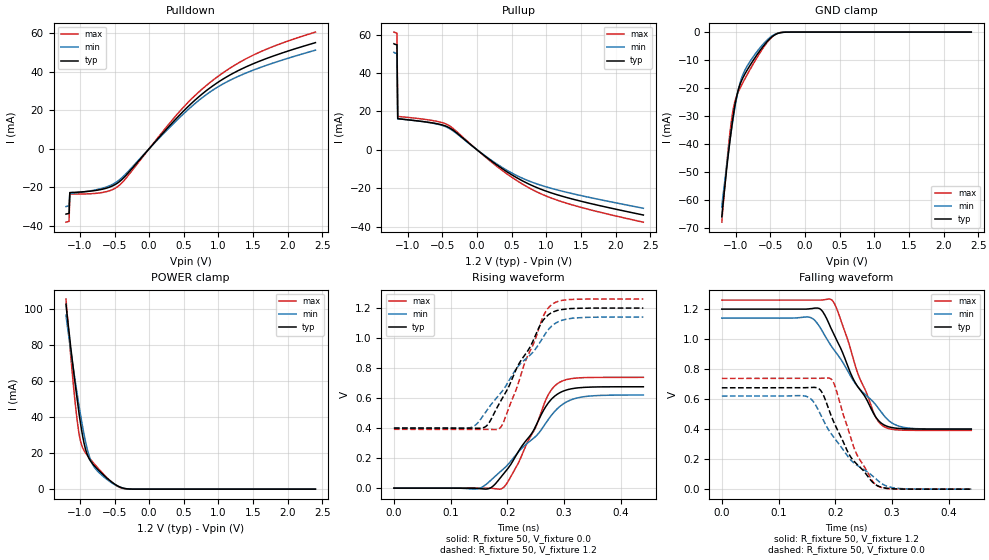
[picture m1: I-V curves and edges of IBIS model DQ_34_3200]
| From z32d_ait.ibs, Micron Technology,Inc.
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| MODEL DQ_34_3200 (34 Ohm Data I/O with no ODT, 1600-3200Mbps)
[Model]   DQ_34_3200
Model_type   I/O
Vinl = 905.000mV
Vinh = 1015.000mV
Vmeas = 960.000mV
Vref = 1200.000mV
Cref = 0.0pF
Rref = 50.000Ohm
|   typ   min   max
|C_comp   0.636pF   0.586pF   0.686pF
C_comp_pullup   0.318pF   0.293pF   0.343pF
C_comp_pulldown   0.318pF   0.293pF   0.343pF
[Model Spec]
| Timing spec test load voltage corners
Vref   1.2000V   1.1400V   1.2600V
| Dynamic Overshoot Parameters from DDR4 Specification
|D_overshoot_ampl_h   0.40   NA   NA
|D_overshoot_ampl_l   0.40   NA   NA
|D_overshoot_area_h   0.0800n   NA   NA
|D_overshoot_area_l   0.0800n   NA   NA
[Voltage Range]   1.2000V   1.1400V   1.2600V
| Junction Temperature (Ambient temp is 35C typ, 95C min, -40C max)
[Temperature Range]   50.0   110.0   -40.0
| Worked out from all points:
|   slope of the pulldown table from 0 to 0.18 V, typ, clamps not added: 24.5 ohm
|   slope of the pullup table from 0 to 0.18 V, typ, clamps not added: 35.6 ohm
|   GND clamp passes 1 mA (typ) near -0.44 V on its own axis
|   POWER clamp passes 1 mA (typ) near -0.41 V on its own axis
|   rising waveform, R_fixture 50, V_fixture 0.0: 20-80 % time 65.4ps typ, 88.1ps min, 51.3ps max; typ from 0 V to 0.675 V
|   rising waveform, R_fixture 50, V_fixture 1.2: 20-80 % time 66.8ps typ, 91.4ps min, 51.8ps max; typ from 0.4 V to 1.2 V
|   falling waveform, R_fixture 50, V_fixture 1.2: 20-80 % time 63.8ps typ, 87.8ps min, 48.9ps max; typ from 1.2 V to 0.4 V
|   falling waveform, R_fixture 50, V_fixture 0.0: 20-80 % time 59ps typ, 79.1ps min, 44.9ps max; typ from 0.676 V to 0 V
[Pulldown]
|   Voltage   I(typ)   I(min)   I(max)
-1.2V     -33.97mA   -30.06mA   -38.16mA
-1.156V   -33.6mA    -29.68mA   -37.79mA
-1.145V   -22.76mA   -23.2mA    -23.52mA
-676.4mV  -21.04mA   -20.54mA   -22.75mA
-545.5mV  -19.58mA   -18.83mA   -21.48mA
-436.4mV  -17.3mA    -16.38mA   -19.17mA
447.3mV   17.75mA    16.45mA    19.64mA
687.3mV   26.05mA    24.22mA    28.48mA
960mV     33.69mA    31.4mA     36.67mA
1.222V    39.38mA    36.53mA    43.11mA
1.527V    44.52mA    41.16mA    49.04mA
2.4V      55.1mA     51.2mA     60.58mA
[GND Clamp]
|   Voltage   I(typ)   I(min)   I(max)
-1.2V     -66.16mA   -62.66mA   -68.09mA
-1.135V   -50.09mA   -48.7mA    -48.84mA
-1.091V   -40.54mA   -40.34mA   -37.85mA
-1.047V   -32.06mA   -32.63mA   -29.28mA
-1.004V   -25.24mA   -25.89mA   -24.15mA
-938.2mV  -18.79mA   -18.38mA   -20.13mA
-850.9mV  -14.31mA   -12.88mA   -15.99mA
-643.6mV  -6.426mA   -5.46mA    -7.18mA
-458.2mV  -1.359mA   -1.119mA   -1.332mA
-381.8mV  -387.1uA   -326.7uA   -300.2uA
-250.9mV  -9.002uA   -11.12uA   1.741uA
2.4V      0A         0A         0A
[Pullup]
|   Voltage   I(typ)   I(min)   I(max)
-1.2V     55.21mA    50.73mA    61.29mA
-1.156V   54.64mA    50.13mA    60.76mA
-1.145V   16.26mA    16.13mA    17.4mA
-643.6mV  14.02mA    13.88mA    15.25mA
-414.5mV  11.76mA    11.38mA    12.86mA
-316.4mV  9.458mA    9.085mA    10.21mA
120mV     -3.407mA   -3.214mA   -3.711mA
370.9mV   -9.995mA   -9.341mA   -10.94mA
654.5mV   -16.13mA   -14.79mA   -17.81mA
960mV     -21.02mA   -18.86mA   -23.48mA
1.484V    -26.6mA    -23.68mA   -29.78mA
2.4V      -33.93mA   -30.41mA   -37.66mA
[POWER Clamp]
|   Voltage   I(typ)   I(min)   I(max)
-1.2V     102.5mA    96.48mA    105.3mA
-1.135V   79.77mA    77.75mA    75.19mA
-1.08V    62.13mA    63.23mA    52.54mA
-1.036V   48.91mA    52.15mA    37.32mA
-992.7mV  37.04mA    41.72mA    27.02mA
-916.4mV  21.89mA    26.01mA    20mA
-829.1mV  14.68mA    14.76mA    15.72mA
-730.9mV  10.5mA     9.465mA    11.33mA
-512.7mV  3.198mA    2.84mA     3.061mA
-392.7mV  773.5uA    737.7uA    533.9uA
-250.9mV  21.9uA     30.56uA    -1.736uA
2.4V      0A         0A         0A
[Ramp]
|   typ   min   max
| 20% - 80%
dV/dt_r   405.29m/65.42p   372.32m/88.07p   442.96m/51.27p
dV/dt_f   479.80m/63.86p   444.02m/87.85p   520.92m/48.87p
| Slew rate: Power terminated
|SR_r[V/ns]   7.18   4.86   10.05
|SR_f[V/ns]   7.51   5.05   10.66
| 25% - 75%
|dV/dt_r   337.74m/54.25p   310.27m/73.21p   369.13m/42.54p
|dV/dt_f   399.83m/53.48p   370.02m/73.44p   434.10m/40.83p
| Slew rate: Power terminated
|SR_r[V/ns]   7.13   4.78   9.99
|SR_f[V/ns]   7.48   5.04   10.63
R_load = 50
[Rising Waveform]
R_fixture = 50
V_fixture = 0.0
|   Time   V(typ)   V(min)   V(max)
0s        5.466uV    13.47uV    320nV
147ps     -1.706mV   -4.715mV   17.38uV
170ps     697.3uV    49.22mV    -380.1uV
190ps     79.57mV    117.2mV    -3.675mV
217ps     227.7mV    229.6mV    148mV
250ps     412.1mV    344.3mV    405.2mV
270ps     555.5mV    444.8mV    605.2mV
287ps     622.8mV    524.8mV    691.8mV
331ps     670.3mV    606.8mV    735.8mV
440ps     675.5mV    620.6mV    738.3mV
[Rising Waveform]
R_fixture   = 50
V_fixture   = 1.2
V_fixture_min = 1.14
V_fixture_max = 1.26
|   Time   V(typ)   V(min)   V(max)
0s        400.3mV    399.9mV    391.8mV
136ps     399.9mV    404.2mV    391.8mV
163ps     413.5mV    514.3mV    391.8mV
185ps     557.9mV    617.9mV    395.1mV
194ps     615.4mV    661.3mV    446mV
218ps     810.6mV    806.5mV    681.6mV
259ps     1.094V     980.3mV    1.102V
276ps     1.164V     1.072V     1.216V
316ps     1.197V     1.133V     1.258V
440ps     1.2V       1.14V      1.26V
[Falling Waveform]
R_fixture   = 50
V_fixture   = 1.2
V_fixture_min = 1.14
V_fixture_max = 1.26
|   Time   V(typ)   V(min)   V(max)
0s        1.2V       1.14V      1.26V
155ps     1.202V     1.146V     1.26V
175ps     1.196V     1.067V     1.26V
192ps     1.077V     960mV      1.265V
205ps     974.9mV    892.3mV    1.18V
233ps     725.6mV    717.6mV    853.4mV
268ps     502mV      578.1mV    507.4mV
281ps     440.7mV    514.9mV    430.7mV
320ps     402.7mV    412.6mV    393.1mV
440ps     400.3mV    400mV      391.8mV
[Falling Waveform]
R_fixture = 50
V_fixture = 0.0
|   Time   V(typ)   V(min)   V(max)
0s        675.5mV    620.6mV    738.3mV
150ps     676.7mV    617.1mV    738.3mV
174ps     659.6mV    497.8mV    738.8mV
191ps     507.9mV    380mV      738mV
200ps     426.2mV    333.1mV    682.6mV
224ps     235.1mV    208.9mV    385.9mV
236ps     175mV      165.6mV    248.3mV
272ps     28.24mV    67.34mV    28.54mV
310ps     1.328mV    5.559mV    665.5uV
440ps     5.568uV    15.11uV    4.257uV
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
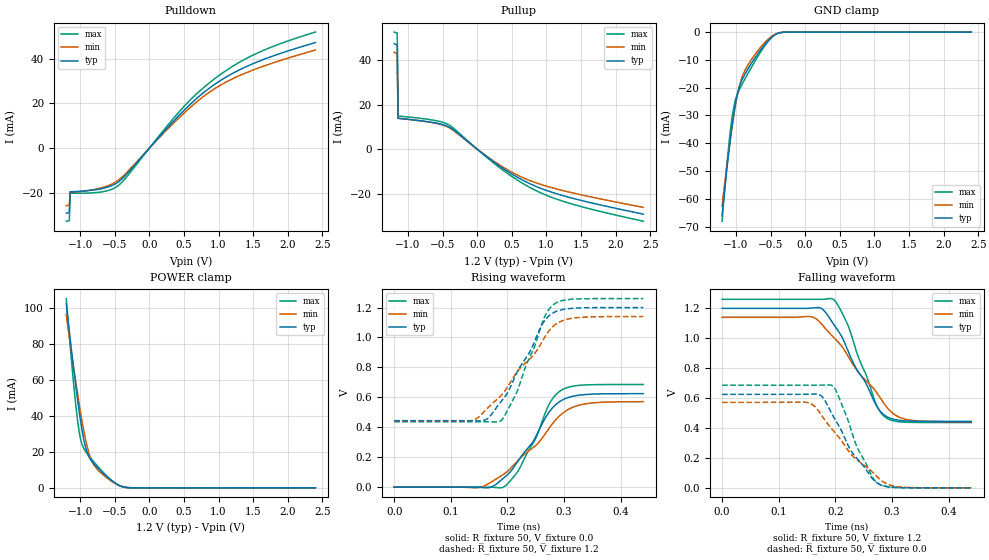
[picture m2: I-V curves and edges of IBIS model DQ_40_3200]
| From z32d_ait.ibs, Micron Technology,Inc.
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| MODEL DQ_40_3200 (40 Ohm Data I/O with no ODT, 1600-3200Mbps)
[Model]   DQ_40_3200
Model_type   I/O
Vinl = 905.000mV
Vinh = 1015.000mV
Vmeas = 960.000mV
Vref = 1200.000mV
Cref = 0.0pF
Rref = 50.000Ohm
|   typ   min   max
|C_comp   0.636pF   0.586pF   0.686pF
C_comp_pullup   0.318pF   0.293pF   0.343pF
C_comp_pulldown   0.318pF   0.293pF   0.343pF
[Model Spec]
| Timing spec test load voltage corners
Vref   1.2000V   1.1400V   1.2600V
| Dynamic Overshoot Parameters from DDR4 Specification
|D_overshoot_ampl_h   0.40   NA   NA
|D_overshoot_ampl_l   0.40   NA   NA
|D_overshoot_area_h   0.0800n   NA   NA
|D_overshoot_area_l   0.0800n   NA   NA
[Voltage Range]   1.2000V   1.1400V   1.2600V
| Junction Temperature (Ambient temp is 35C typ, 95C min, -40C max)
[Temperature Range]   50.0   110.0   -40.0
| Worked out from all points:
|   slope of the pulldown table from 0 to 0.18 V, typ, clamps not added: 28.6 ohm
|   slope of the pullup table from 0 to 0.18 V, typ, clamps not added: 41.6 ohm
|   GND clamp passes 1 mA (typ) near -0.44 V on its own axis
|   POWER clamp passes 1 mA (typ) near -0.41 V on its own axis
|   rising waveform, R_fixture 50, V_fixture 0.0: 20-80 % time 63.6ps typ, 84.2ps min, 49.8ps max; typ from 0 V to 0.625 V
|   rising waveform, R_fixture 50, V_fixture 1.2: 20-80 % time 62.3ps typ, 85.2ps min, 48.6ps max; typ from 0.444 V to 1.2 V
|   falling waveform, R_fixture 50, V_fixture 1.2: 20-80 % time 61.1ps typ, 84.5ps min, 46.3ps max; typ from 1.2 V to 0.444 V
|   falling waveform, R_fixture 50, V_fixture 0.0: 20-80 % time 60.7ps typ, 82.4ps min, 45.1ps max; typ from 0.625 V to 0 V
[Pulldown]
|   Voltage   I(typ)   I(min)   I(max)
-1.2V     -29.12mA   -25.76mA   -32.71mA
-1.156V   -28.8mA    -25.44mA   -32.39mA
-1.145V   -19.51mA   -19.88mA   -20.16mA
-698.2mV  -18.17mA   -17.78mA   -19.61mA
-447.3mV  -15.08mA   -14.3mA    -16.69mA
-338.2mV  -11.99mA   -11.26mA   -13.27mA
469.1mV   15.9mA     14.73mA    17.58mA
698.2mV   22.62mA    21.06mA    24.73mA
949.1mV   28.64mA    26.71mA    31.17mA
1.233V    33.94mA    31.47mA    37.16mA
1.527V    38.16mA    35.28mA    42.03mA
2.4V      47.23mA    43.88mA    51.93mA
[GND Clamp]
|   Voltage   I(typ)   I(min)   I(max)
-1.2V     -66.16mA   -62.66mA   -68.09mA
-1.135V   -50.09mA   -48.7mA    -48.84mA
-1.091V   -40.55mA   -40.34mA   -37.85mA
-1.047V   -32.05mA   -32.63mA   -29.3mA
-1.004V   -25.21mA   -25.91mA   -24.13mA
-970.9mV  -21.44mA   -21.67mA   -21.89mA
-927.3mV  -18.1mA    -17.42mA   -19.59mA
-850.9mV  -14.3mA    -12.88mA   -15.99mA
-632.7mV  -6.061mA   -5.136mA   -6.759mA
-447.3mV  -1.181mA   -961.6uA   -1.122mA
-250.9mV  -9.403uA   -12.65uA   310.9nA
2.4V      0A         0A         0A
[Pullup]
|   Voltage   I(typ)   I(min)   I(max)
-1.2V     47.33mA    43.48mA    52.54mA
-1.156V   46.84mA    42.97mA    52.08mA
-1.145V   13.94mA    13.83mA    14.91mA
-643.6mV  12.01mA    11.9mA     13.07mA
-425.5mV  10.24mA    9.925mA    11.21mA
-316.4mV  8.104mA    7.779mA    8.758mA
43.64mV   -1.073mA   -1.015mA   -1.164mA
370.9mV   -8.572mA   -8.003mA   -9.376mA
621.8mV   -13.28mA   -12.21mA   -14.64mA
960mV     -18.01mA   -16.17mA   -20.13mA
1.462V    -22.63mA   -20.14mA   -25.34mA
2.4V      -29.08mA   -26.07mA   -32.28mA
[POWER Clamp]
|   Voltage   I(typ)   I(min)   I(max)
-1.2V     102.5mA    96.48mA    105.3mA
-1.135V   79.77mA    77.75mA    75.19mA
-1.069V   58.73mA    60.41mA    48.42mA
-1.015V   42.78mA    46.83mA    31.4mA
-981.8mV  34.36mA    39.25mA    25.35mA
-938.2mV  25.27mA    30.08mA    21.3mA
-905.5mV  20.47mA    24.14mA    19.42mA
-818.2mV  14.14mA    13.89mA    15.22mA
-709.1mV  9.665mA    8.657mA    10.4mA
-501.8mV  2.908mA    2.591mA    2.742mA
-250.9mV  22.56uA    34.23uA    -929.3nA
2.4V      0A         0A         0A
[Ramp]
|   typ   min   max
| 20% - 80%
dV/dt_r   374.75m/63.58p   342.62m/84.23p   411.51m/49.79p
dV/dt_f   453.55m/61.15p   418.58m/84.59p   494.02m/46.30p
| 25% - 75%
|dV/dt_r   312.29m/52.61p   285.52m/70.40p   342.92m/41.18p
|dV/dt_f   377.96m/50.69p   348.81m/69.36p   411.68m/38.61p
R_load = 50
[Rising Waveform]
R_fixture = 50
V_fixture = 0.0
|   Time   V(typ)   V(min)   V(max)
0s        6.048uV    14.58uV    354.8nV
148ps     -1.045mV   -3.73mV    7.131uV
171ps     -47.82uV   33.03mV    -174.4uV
192ps     56.09mV    82.32mV    -1.231mV
220ps     183mV      183.4mV    115.5mV
250ps     337mV      278.3mV    326.2mV
273ps     498.3mV    390.8mV    549.3mV
292ps     570.9mV    476.1mV    639.7mV
336ps     618.4mV    555.5mV    682.6mV
440ps     624.6mV    571mV      685.8mV
[Rising Waveform]
R_fixture   = 50
V_fixture   = 1.2
V_fixture_min = 1.14
V_fixture_max = 1.26
|   Time   V(typ)   V(min)   V(max)
0s        444.1mV    442.3mV    436.6mV
137ps     443.8mV    445.3mV    436.6mV
164ps     455.2mV    524.7mV    436.6mV
187ps     563.5mV    604.8mV    440.8mV
215ps     752.6mV    760mV      620.6mV
240ps     907.8mV    857.9mV    872.9mV
264ps     1.104V     990.6mV    1.125V
279ps     1.161V     1.069V     1.213V
320ps     1.197V     1.132V     1.257V
440ps     1.2V       1.14V      1.26V
[Falling Waveform]
R_fixture   = 50
V_fixture   = 1.2
V_fixture_min = 1.14
V_fixture_max = 1.26
|   Time   V(typ)   V(min)   V(max)
0s        1.2V       1.14V      1.26V
156ps     1.201V     1.145V     1.26V
176ps     1.198V     1.093V     1.26V
195ps     1.104V     1.012V     1.263V
220ps     936.8mV    895.9mV    1.107V
270ps     566.7mV    651.7mV    576.7mV
286ps     487.8mV    563.5mV    478.6mV
304ps     457.1mV    491mV      446.5mV
327ps     446.9mV    455.9mV    438.2mV
440ps     444.1mV    442.4mV    436.6mV
[Falling Waveform]
R_fixture = 50
V_fixture = 0.0
|   Time   V(typ)   V(min)   V(max)
0s        624.6mV    571.2mV    685.9mV
151ps     625.4mV    569.7mV    685.8mV
175ps     614.8mV    488.2mV    686.2mV
193ps     500.6mV    397.3mV    685.8mV
203ps     434.8mV    352.8mV    635mV
229ps     239.7mV    219mV      371.8mV
241ps     184.3mV    178.6mV    251.3mV
275ps     29.84mV    69.66mV    30.19mV
313ps     1.736mV    6.587mV    945.6uV
440ps     6.181uV    17.23uV    368.3nV
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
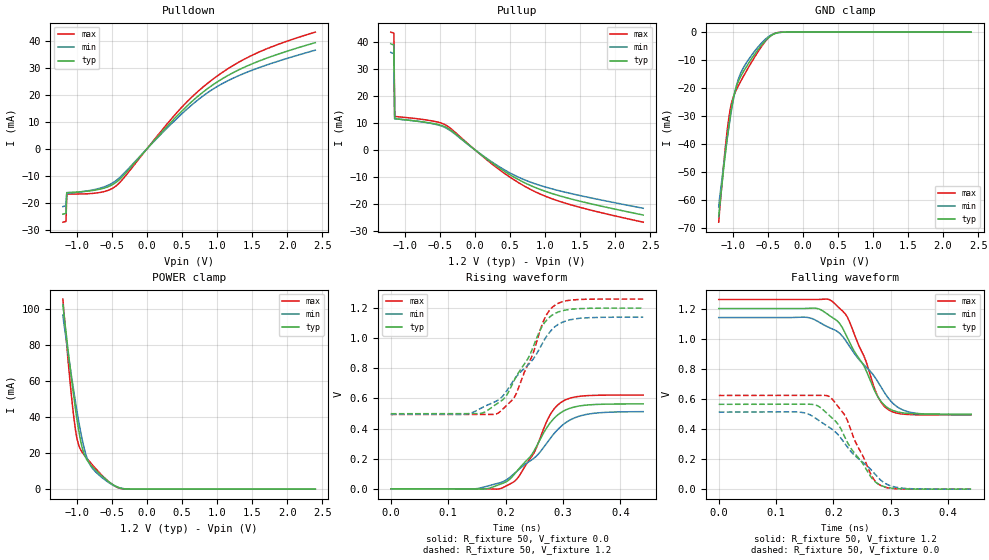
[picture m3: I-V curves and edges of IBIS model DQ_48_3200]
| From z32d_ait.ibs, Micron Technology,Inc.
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| MODEL DQ_48_3200 (48 Ohm Data I/O with no ODT, 1600-3200Mbps)
[Model]   DQ_48_3200
Model_type   I/O
Vinl = 905.000mV
Vinh = 1015.000mV
Vmeas = 960.000mV
Vref = 1200.000mV
Cref = 0.0pF
Rref = 50.000Ohm
|   typ   min   max
|C_comp   0.636pF   0.586pF   0.686pF
C_comp_pullup   0.318pF   0.293pF   0.343pF
C_comp_pulldown   0.318pF   0.293pF   0.343pF
[Model Spec]
| Timing spec test load voltage corners
Vref   1.2000V   1.1400V   1.2600V
| Dynamic Overshoot Parameters from DDR4 Specification
|D_overshoot_ampl_h   0.40   NA   NA
|D_overshoot_ampl_l   0.40   NA   NA
|D_overshoot_area_h   0.0800n   NA   NA
|D_overshoot_area_l   0.0800n   NA   NA
[Voltage Range]   1.2000V   1.1400V   1.2600V
| Junction Temperature (Ambient temp is 35C typ, 95C min, -40C max)
[Temperature Range]   50.0   110.0   -40.0
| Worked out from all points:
|   slope of the pulldown table from 0 to 0.18 V, typ, clamps not added: 34.3 ohm
|   slope of the pullup table from 0 to 0.18 V, typ, clamps not added: 49.8 ohm
|   GND clamp passes 1 mA (typ) near -0.44 V on its own axis
|   POWER clamp passes 1 mA (typ) near -0.41 V on its own axis
|   rising waveform, R_fixture 50, V_fixture 0.0: 20-80 % time 61.7ps typ, 79.8ps min, 48.6ps max; typ from 0 V to 0.564 V
|   rising waveform, R_fixture 50, V_fixture 1.2: 20-80 % time 56.5ps typ, 74.2ps min, 45ps max; typ from 0.499 V to 1.2 V
|   falling waveform, R_fixture 50, V_fixture 1.2: 20-80 % time 56.4ps typ, 75.3ps min, 45.2ps max; typ from 1.2 V to 0.499 V
|   falling waveform, R_fixture 50, V_fixture 0.0: 20-80 % time 56.3ps typ, 78.7ps min, 43.6ps max; typ from 0.564 V to 0 V
[Pulldown]
|   Voltage   I(typ)   I(min)   I(max)
-1.2V     -24.27mA   -21.47mA   -27.26mA
-1.156V   -24mA      -21.2mA    -26.99mA
-1.145V   -16.26mA   -16.57mA   -16.8mA
-665.5mV  -14.96mA   -14.59mA   -16.2mA
-545.5mV  -13.99mA   -13.45mA   -15.35mA
-436.4mV  -12.37mA   -11.7mA    -13.68mA
425.5mV   12.1mA     11.21mA    13.4mA
643.6mV   17.6mA     16.36mA    19.29mA
927.3mV   23.48mA    21.9mA     25.55mA
1.2V      27.83mA    25.82mA    30.45mA
1.527V    31.8mA     29.41mA    35.03mA
2.4V      39.36mA    36.57mA    43.27mA
[GND Clamp]
|   Voltage   I(typ)   I(min)   I(max)
-1.2V     -66.16mA   -62.66mA   -68.09mA
-1.135V   -50.09mA   -48.7mA    -48.85mA
-1.091V   -40.54mA   -40.34mA   -37.85mA
-1.058V   -34.05mA   -34.49mA   -31.11mA
-1.015V   -26.75mA   -27.46mA   -25.14mA
-981.8mV  -22.6mA    -23mA      -22.55mA
-949.1mV  -19.59mA   -19.34mA   -20.69mA
-861.8mV  -14.78mA   -13.39mA   -16.49mA
-654.5mV  -6.796mA   -5.791mA   -7.607mA
-458.2mV  -1.354mA   -1.107mA   -1.328mA
-261.8mV  -15.07uA   -18.95uA   -1.874uA
2.4V      0A         0A         0A
[Pullup]
|   Voltage   I(typ)   I(min)   I(max)
-1.2V     39.44mA    36.24mA    43.78mA
-1.156V   39.03mA    35.81mA    43.4mA
-1.145V   11.61mA    11.52mA    12.43mA
-665.5mV  10.1mA     10.02mA    10.99mA
-425.5mV  8.536mA    8.269mA    9.339mA
-327.3mV  6.972mA    6.698mA    7.536mA
43.64mV   -895.4uA   -845.9uA   -972.5uA
349.1mV   -6.756mA   -6.322mA   -7.395mA
665.5mV   -11.66mA   -10.69mA   -12.88mA
949.1mV   -14.91mA   -13.39mA   -16.65mA
1.462V    -18.86mA   -16.79mA   -21.12mA
2.4V      -24.24mA   -21.72mA   -26.9mA
[POWER Clamp]
|   Voltage   I(typ)   I(min)   I(max)
-1.2V     102.5mA    96.48mA    105.3mA
-1.135V   79.77mA    77.75mA    75.19mA
-1.069V   58.73mA    60.41mA    48.4mA
-1.015V   42.76mA    46.83mA    31.44mA
-981.8mV  34.37mA    39.24mA    25.34mA
-938.2mV  25.23mA    30.06mA    21.29mA
-905.5mV  20.47mA    24.12mA    19.42mA
-818.2mV  14.14mA    13.89mA    15.22mA
-709.1mV  9.665mA    8.657mA    10.4mA
-501.8mV  2.9mA      2.591mA    2.745mA
-261.8mV  34uA       48.13uA    4.604uA
2.4V      0A         0A         0A
[Ramp]
|   typ   min   max
| 20% - 80%
dV/dt_r   338.19m/61.67p   307.28m/79.81p   373.57m/48.65p
dV/dt_f   420.87m/56.38p   387.18m/75.31p   460.07m/45.24p
| 25% - 75%
|dV/dt_r   281.82m/49.79p   256.07m/65.67p   311.31m/39.25p
|dV/dt_f   350.73m/47.52p   322.65m/63.67p   383.39m/37.68p
R_load = 50
[Rising Waveform]
R_fixture = 50
V_fixture = 0.0
|   Time   V(typ)   V(min)   V(max)
0s        6.769uV    16.18uV    398.2nV
143ps     -458.5uV   -1.685mV   -2.739uV
193ps     32.9mV     43.31mV    3.811mV
207ps     62.53mV    74.26mV    30.62mV
223ps     131.7mV    128.2mV    80.82mV
251ps     260.6mV    207.6mV    248.6mV
277ps     433.9mV    330.3mV    486.6mV
298ps     509.5mV    418.8mV    577.1mV
346ps     557.5mV    497.2mV    619.4mV
440ps     563.7mV    512.2mV    622.6mV
[Rising Waveform]
R_fixture   = 50
V_fixture   = 1.2
V_fixture_min = 1.14
V_fixture_max = 1.26
|   Time   V(typ)   V(min)   V(max)
0s        498.5mV    494.7mV    493.2mV
132ps     498.4mV    496.7mV    493.2mV
186ps     566.9mV    586.3mV    500.2mV
201ps     616.4mV    644.5mV    551.7mV
217ps     734.3mV    735.5mV    618.8mV
248ps     939.9mV    860.4mV    899.5mV
267ps     1.098V     984.5mV    1.122V
286ps     1.164V     1.076V     1.219V
328ps     1.196V     1.132V     1.257V
440ps     1.2V       1.14V      1.26V
[Falling Waveform]
R_fixture   = 50
V_fixture   = 1.2
V_fixture_min = 1.14
V_fixture_max = 1.26
|   Time   V(typ)   V(min)   V(max)
0s        1.2V       1.14V      1.26V
153ps     1.201V     1.142V     1.26V
193ps     1.153V     1.073V     1.259V
211ps     1.1V       1.035V     1.2V
224ps     1.008V     972mV      1.145V
255ps     804.3mV    818.7mV    867mV
275ps     629.7mV    727.9mV    635.9mV
292ps     547.6mV    623.9mV    538.7mV
332ps     502.8mV    512.6mV    495.8mV
440ps     498.5mV    494.7mV    493.2mV
[Falling Waveform]
R_fixture = 50
V_fixture = 0.0
|   Time   V(typ)   V(min)   V(max)
0s        563.7mV    512.4mV    622.6mV
144ps     564.1mV    510.5mV    622.6mV
171ps     556.2mV    465.4mV    622.9mV
191ps     495.2mV    415.3mV    618.5mV
208ps     431.6mV    362.1mV    548.8mV
220ps     344.5mV    301.3mV    489.3mV
265ps     83.15mV    131.4mV    100.1mV
280ps     30.02mV    68.61mV    29.53mV
320ps     1.953mV    6.822mV    1.095mV
440ps     7.785uV    18.3uV     515.6nV
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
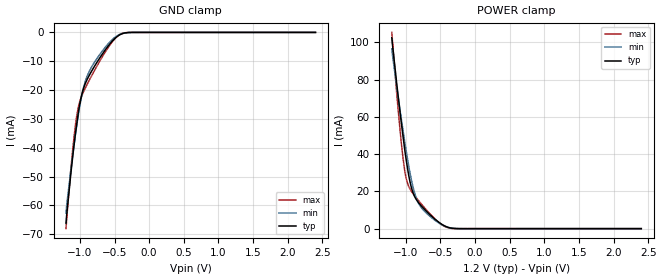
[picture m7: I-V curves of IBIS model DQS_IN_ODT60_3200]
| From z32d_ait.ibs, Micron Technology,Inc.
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| MODEL DQS_IN_ODT60_3200 (Data Strobe Input with 60ohm ODT, 1600-3200Mbps)
[Model]   DQS_IN_ODT60_3200
Model_type   Input
Vinl = 905.000mV
Vinh = 1015.000mV
|   typ   min   max
|C_comp   0.596pF   0.538pF   0.646pF
C_comp_power_clamp   0.298pF   0.269pF   0.323pF
C_comp_gnd_clamp   0.298pF   0.269pF   0.323pF
| Note: C_comp changes when the ODT circuit is enabled.
|[Model Spec]
| Dynamic Overshoot Parameters from DDR4 Specification
|D_overshoot_ampl_h   0.40   NA   NA
|D_overshoot_ampl_l   0.40   NA   NA
|D_overshoot_area_h   0.0800n   NA   NA
|D_overshoot_area_l   0.0800n   NA   NA
[Voltage Range]   1.2000V   1.1400V   1.2600V
| Junction Temperature (Ambient temp is 35C typ, 95C min, -40C max)
[Temperature Range]   50.0   110.0   -40.0
[Add Submodel]
| Submodel Name   Mode
60ohm_ODT_3200   Non-Driving
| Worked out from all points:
|   GND clamp passes 1 mA (typ) near -0.44 V on its own axis
|   POWER clamp passes 1 mA (typ) near -0.41 V on its own axis
[GND Clamp]
|   Voltage   I(typ)   I(min)   I(max)
-1.2V     -66.16mA   -62.66mA   -68.09mA
-1.135V   -50.09mA   -48.7mA    -48.84mA
-1.091V   -40.54mA   -40.34mA   -37.85mA
-1.047V   -32.06mA   -32.63mA   -29.28mA
-1.004V   -25.24mA   -25.89mA   -24.15mA
-938.2mV  -18.79mA   -18.38mA   -20.13mA
-850.9mV  -14.31mA   -12.88mA   -15.99mA
-643.6mV  -6.426mA   -5.46mA    -7.18mA
-458.2mV  -1.359mA   -1.119mA   -1.332mA
-381.8mV  -387.1uA   -326.7uA   -300.2uA
-250.9mV  -9.002uA   -11.12uA   1.741uA
2.4V      0A         0A         0A
[POWER Clamp]
|   Voltage   I(typ)   I(min)   I(max)
-1.2V     102.5mA    96.48mA    105.3mA
-1.135V   79.77mA    77.75mA    75.19mA
-1.08V    62.13mA    63.23mA    52.54mA
-1.036V   48.91mA    52.15mA    37.32mA
-992.7mV  37.04mA    41.72mA    27.02mA
-916.4mV  21.89mA    26.01mA    20mA
-829.1mV  14.68mA    14.76mA    15.72mA
-730.9mV  10.5mA     9.465mA    11.33mA
-512.7mV  3.198mA    2.84mA     3.061mA
-392.7mV  773.5uA    737.7uA    533.9uA
-250.9mV  21.9uA     30.56uA    -1.736uA
2.4V      0A         0A         0A
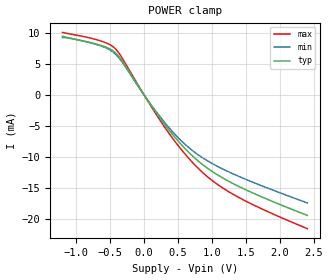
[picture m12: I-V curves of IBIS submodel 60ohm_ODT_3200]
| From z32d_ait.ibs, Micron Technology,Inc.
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| SUBMODEL 60ohm_ODT_3200
[Submodel]   60ohm_ODT_3200
Submodel_type  Dynamic_clamp
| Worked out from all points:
|   POWER clamp passes 1 mA (typ) near -0.06 V on its own axis
[POWER Clamp]
|   Voltage   I(typ)   I(min)   I(max)
-1.2V     9.457mA    9.239mA    10.08mA
-660mV    8.062mA    7.992mA    8.771mA
-510mV    7.447mA    7.297mA    8.139mA
-415mV    6.72mA     6.505mA    7.359mA
-315mV    5.383mA    5.169mA    5.811mA
105mV     -1.705mA   -1.613mA   -1.857mA
420mV     -6.378mA   -5.948mA   -6.986mA
695mV     -9.64mA    -8.815mA   -10.66mA
940mV     -11.85mA   -10.65mA   -13.24mA
1.16V     -13.38mA   -11.94mA   -15mA
1.455V    -15.06mA   -13.4mA    -16.86mA
2.4V      -19.39mA   -17.38mA   -21.52mA
